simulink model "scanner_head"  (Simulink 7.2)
settings: Solver=FixedStepDiscrete  SolverMode=SingleTasking  StartTime=0  StopTime=500  FixedStep=0.004  RelTol=1e-3
PreLoadFcn:
  | scanner_head_prm;
  | xlsreadsdo('nxtscanner.xls','mpt');
undefined symbols (not defined in the file or in its folder): BACKLASH_ADJUST, RELEASE_TOUCH_SENSOR, SCAN_EDGE, SCAN_F_TIMEOUT, SCAN_INITIALIZE_PWM, SCAN_INITIALIZE_TIMEOUT, SCAN_L_MAX_PWM, SCAN_L_MIN_PWM, SCAN_L_TIMEOUT, SCAN_R_MAX_PWM, SCAN_R_MIN_PWM, SCAN_R_TIMEOUT, SCAN_START, ScannerBufferInfoEnum, sigbuilder_block
libraries: simulink x1

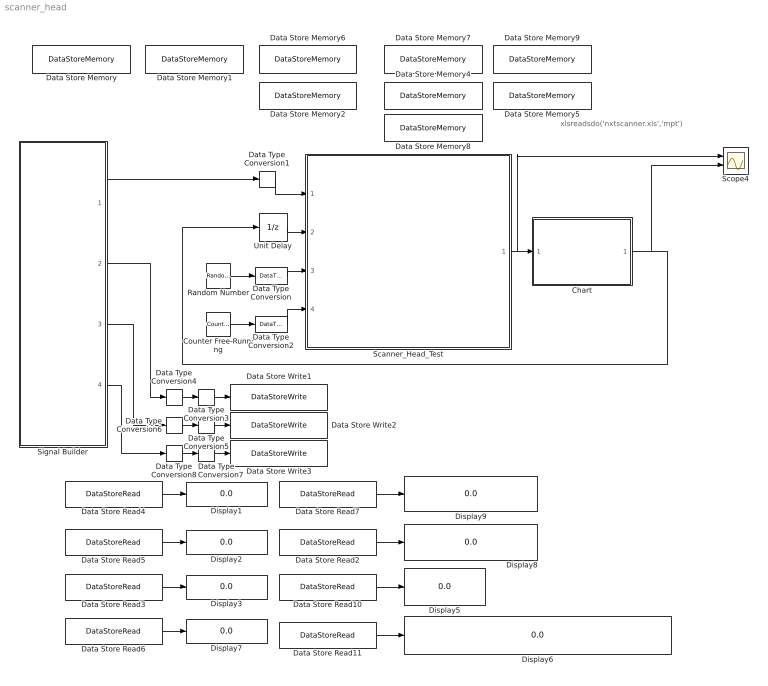
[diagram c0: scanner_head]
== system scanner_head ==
  note: xlsreadsdo('nxtscanner.xls','mpt')
  Chart : Stateflow chart
  Counter Free-Running : simulink/Sources/Counter Free-Running  SystemSampleTime=-1  NumBits=32  tsamp=-1
  Data Store Memory : DataStoreMemory  DataStoreName=ControlMode  ReadBeforeWriteMsg=warning  WriteAfterWriteMsg=warning  WriteAfterReadMsg=warning  InitialValue=ControlModeEnum.INITIALIZE  DataType=Specify via dialog  OutDataType=Enum: ControlModeEnum  OutDataTypeStr=Enum: ControlModeEnum
  Data Store Memory1 : DataStoreMemory  DataStoreName=ErrorCode  ReadBeforeWriteMsg=warning  WriteAfterWriteMsg=warning  WriteAfterReadMsg=warning  InitialValue=ErrorCodeEnum.NO_ERROR  DataType=Specify via dialog  OutDataType=Enum: ErrorCodeEnum  OutDataTypeStr=Enum: ErrorCodeEnum
  Data Store Memory2 : DataStoreMemory  DataStoreName=FeedMode  ReadBeforeWriteMsg=warning  WriteAfterWriteMsg=warning  WriteAfterReadMsg=warning  InitialValue=FeedModeEnum.FEED_IDLE  DataType=Specify via dialog  OutDataType=Enum: FeedModeEnum  OutDataTypeStr=Enum: FeedModeEnum
  Data Store Memory4 : DataStoreMemory  DataStoreName=ScannerBuffer_Number  ReadBeforeWriteMsg=warning  WriteAfterWriteMsg=warning  WriteAfterReadMsg=warning  InitialValue=[0;0]  DataType=uint8  OutDataType=Enum: FeedModeEnum  OutDataTypeStr=uint8
  Data Store Memory5 : DataStoreMemory  DataStoreName=ScannerBuffer_Data  ReadBeforeWriteMsg=warning  WriteAfterWriteMsg=warning  WriteAfterReadMsg=warning  InitialValue=[0 0 0 0 0 0 0 0 0 0 0 0 0 0 0 0 0 0 0 0 0 0 0 0 0 0 0 0 0 0; 0 0 0 0 0 0 0 0 0 0 0 0 0 0 0 0 0 0 0 0 0 0 0 0 0 0 0 0 0 0]  DataType=uint16  OutDataType=Enum: FeedModeEnum  OutDataTypeStr=uint16
  Data Store Memory6 : DataStoreMemory  DataStoreName=ScanMode  ReadBeforeWriteMsg=warning  WriteAfterWriteMsg=warning  WriteAfterReadMsg=warning  InitialValue=ScanModeEnum.SCAN_INIT  DataType=Specify via dialog  OutDataType=Enum: ScanModeEnum  OutDataTypeStr=Enum: ScanModeEnum
  Data Store Memory7 : DataStoreMemory  DataStoreName=ScannerBuffer_Info  ReadBeforeWriteMsg=warning  WriteAfterWriteMsg=warning  WriteAfterReadMsg=warning  InitialValue=[ScannerBufferInfoEnum.TRANS_FINISH;ScannerBufferInfoEnum.TRANS_FINISH]  DataType=Specify via dialog  OutDataType=Enum: ScannerBufferInfoEnum  OutDataTypeStr=Enum: ScannerBufferInfoEnum
  Data Store Memory8 : DataStoreMemory  DataStoreName=ScannerBuffer_Pnum  ReadBeforeWriteMsg=warning  WriteAfterWriteMsg=warning  WriteAfterReadMsg=warning  InitialValue=[0;0]  DataType=uint8  OutDataType=Enum: FeedModeEnum  OutDataTypeStr=uint8
  Data Store Memory9 : DataStoreMemory  DataStoreName=ScannerBuffer_Status  ReadBeforeWriteMsg=warning  WriteAfterWriteMsg=warning  WriteAfterReadMsg=warning  InitialValue=[0 ;0]  DataType=uint16  OutDataType=Enum: ScannerBufferStatusEnum  OutDataTypeStr=uint16
  Data Store Read10 : DataStoreRead  DataStoreName=ScannerBuffer_Number  SampleTime=0.004
  Data Store Read11 : DataStoreRead  DataStoreName=ScannerBuffer_Data  SampleTime=0.004
  Data Store Read2 : DataStoreRead  DataStoreName=ScannerBuffer_Status  SampleTime=0.004
  Data Store Read3 : DataStoreRead  DataStoreName=ErrorCode  SampleTime=0.004
  Data Store Read4 : DataStoreRead  DataStoreName=ControlMode  SampleTime=0.004
  Data Store Read5 : DataStoreRead  DataStoreName=FeedMode  SampleTime=0.004
  Data Store Read6 : DataStoreRead  DataStoreName=ScanMode  SampleTime=0.004
  Data Store Read7 : DataStoreRead  DataStoreName=ScannerBuffer_Info  SampleTime=0.004
  Data Store Write1 : DataStoreWrite  DataStoreName=ControlMode  SampleTime=-1
  Data Store Write2 : DataStoreWrite  DataStoreName=FeedMode  SampleTime=-1
  Data Store Write3 : DataStoreWrite  DataStoreName=ErrorCode  SampleTime=-1
  Data Type Conversion : DataTypeConversion  OutDataTypeMode=uint16  OutDataType=sfix(16)  OutScaling=2^0  OutDataTypeStr=uint16
  Data Type Conversion{1,3,5,7} (4 alike) : DataTypeConversion  OutDataType=sfix(16)  OutScaling=2^0
  Data Type Conversion2 : DataTypeConversion  OutDataTypeMode=uint32  OutDataType=sfix(16)  OutScaling=2^0  OutDataTypeStr=uint32
  Data Type Conversion4 : DataTypeConversion  OutDataTypeMode=int8  OutDataType=sfix(16)  OutScaling=2^0  OutDataTypeStr=int8
  Data Type Conversion6 : DataTypeConversion  OutDataTypeMode=int8  OutDataType=sfix(16)  OutScaling=2^0  OutDataTypeStr=int8
  Data Type Conversion8 : DataTypeConversion  OutDataTypeMode=int8  OutDataType=sfix(16)  OutScaling=2^0  OutDataTypeStr=int8
  Display{1..3,5..9} (8 alike) : Display
  Random Number : RandomNumber  Mean=1000  Variance=500  SampleTime=0.004
  Scanner_Head_Test : Subsystem
  Scope4 : Scope  NumInputPorts=2
  Signal Builder : Subsystem  Tag=STV Subsys  LoadFcn=sigbuilder_block('load',[199.5 39.75 666 664.5 ]);  StartFcn=sigbuilder_block('start');  StopFcn=sigbuilder_block('stop');  ClipboardFcn=sigbuilder_block('clipboard');
  Unit Delay : UnitDelay  SampleTime=-1
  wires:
  Random Number/1 -> Data Type Conversion/1
  Data Store Read3/1 -> Display3/1
  Data Type Conversion/1 -> Scanner_Head_Test/3(LightSensor)
  Data Store Read4/1 -> Display1/1
  Data Store Read5/1 -> Display2/1
  Data Store Read10/1 -> Display5/1
  Data Store Read11/1 -> Display6/1
  Data Store Read6/1 -> Display7/1
  Chart/1(Encoder_test) -> Unit Delay/1, Scope4/2
  Scanner_Head_Test/1(PWM) -> Chart/1(pwm), Scope4/1
  Data Store Read2/1 -> Display8/1
  Data Store Read7/1 -> Display9/1
  Unit Delay/1 -> Scanner_Head_Test/2(Encoder)
  Counter Free-Running/1 -> Data Type Conversion2/1
  Data Type Conversion2/1 -> Scanner_Head_Test/4(SystemClock)
  Signal Builder/1(SW) -> Data Type Conversion1/1
  Signal Builder/4(ErrorCode) -> Data Type Conversion8/1
  Signal Builder/2(ControlMode) -> Data Type Conversion4/1
  Data Type Conversion3/1 -> Data Store Write1/1
  Data Type Conversion4/1 -> Data Type Conversion3/1
  Data Type Conversion6/1 -> Data Type Conversion5/1
  Data Type Conversion5/1 -> Data Store Write2/1
  Signal Builder/3(FeedMode) -> Data Type Conversion6/1
  Data Type Conversion7/1 -> Data Store Write3/1
  Data Type Conversion8/1 -> Data Type Conversion7/1
  Data Type Conversion1/1 -> Scanner_Head_Test/1(SW)

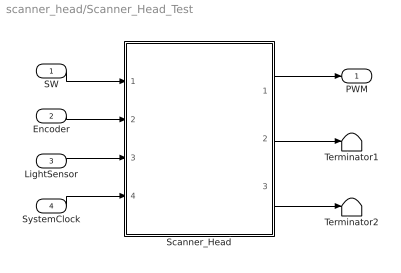
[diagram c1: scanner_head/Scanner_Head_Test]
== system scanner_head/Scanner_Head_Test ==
  SW : Inport
  Encoder : Inport  Port=2
  LightSensor : Inport  Port=3
  SystemClock : Inport  Port=4
  Scanner_Head : Subsystem  TreatAsAtomicUnit=on
  Terminator1 : Terminator
  Terminator2 : Terminator
  PWM : Outport  OutDataType=sfix(16)  OutScaling=2^0
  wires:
  SW/1 -> Scanner_Head/1(Touch)
  Encoder/1 -> Scanner_Head/2(Encoder)
  LightSensor/1 -> Scanner_Head/3(LightSensor)
  Scanner_Head/1(PWM) -> PWM/1
  Scanner_Head/2(now_position) -> Terminator1/1
  SystemClock/1 -> Scanner_Head/4(SystemClock)
  Scanner_Head/3(encoder_base) -> Terminator2/1

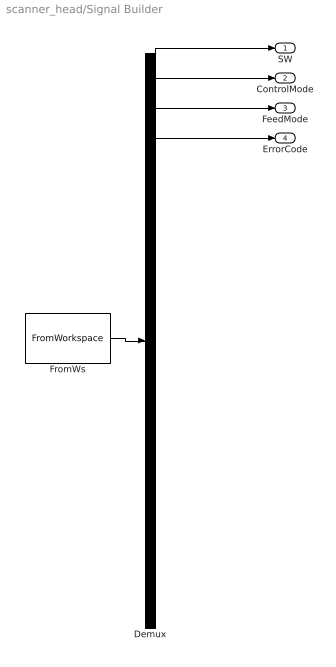
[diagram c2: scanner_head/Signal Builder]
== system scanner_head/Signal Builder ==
  Demux : Demux  Tag=STV Demux
  FromWs : FromWorkspace  Tag=STV FromWs  VariableName=tuvar  SampleTime=0  SigBuilderData=DataTag0  VnvData=DataTag1
  SW : Outport  Tag=STV Outport  OutDataType=sfix(16)  OutScaling=2^0
  ControlMode : Outport  Tag=STV Outport  Port=2
  FeedMode : Outport  Tag=STV Outport  Port=3
  ErrorCode : Outport  Tag=STV Outport  Port=4
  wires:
  FromWs/1 -> Demux/1
  Demux/1 -> SW/1
  Demux/2 -> ControlMode/1
  Demux/3 -> FeedMode/1
  Demux/4 -> ErrorCode/1

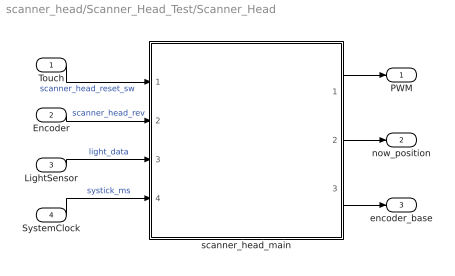
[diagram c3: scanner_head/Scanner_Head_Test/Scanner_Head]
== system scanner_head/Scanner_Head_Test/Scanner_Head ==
  Touch : Inport
  Encoder : Inport  Port=2
  LightSensor : Inport  Port=3
  SystemClock : Inport  Port=4
  scanner_head_main : Stateflow chart
  PWM : Outport  OutDataType=sfix(16)  OutScaling=2^0
  now_position : Outport  Port=2  OutDataType=sfix(16)  OutScaling=2^0
  encoder_base : Outport  Port=3  OutDataType=sfix(16)  OutScaling=2^0
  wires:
  Touch/1 -> scanner_head_main/1(touch_in)  "scanner_head_reset_sw"
  Encoder/1 -> scanner_head_main/2(encoder_in)  "scanner_head_rev"
  LightSensor/1 -> scanner_head_main/3(lightsensor_in)  "light_data"
  scanner_head_main/1(pwm_out) -> PWM/1
  scanner_head_main/2(now_position) -> now_position/1
  scanner_head_main/3(encoder_base) -> encoder_base/1
  SystemClock/1 -> scanner_head_main/4(system_clock_in)  "systick_ms"

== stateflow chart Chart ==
  (default) -> (junction 3)
  (junction 3) -> (junction 4) : [pwm < 0]
  (junction 4) -> (junction 5) : { % 右へ移動 Encoder_test = Encoder_test -3; }
  (junction 6) -> (junction 9)
  (junction 5) -> (junction 8)
  (junction 8) -> (junction 9)
  (junction 7) -> (junction 8) : { % 左へ移動 Encoder_test = Encoder_test +3; }
  (junction 3) -> (junction 6)
  (junction 6) -> (junction 7) : [pwm > 0]
  (junction 9) -> (junction 13)
  (junction 13) -> (junction 12) : [FeedMode == FEED_PAPERFEED ]
  (junction 12) -> (junction 11) : { % 強制紙送り完了させる FeedMode = FEED_IDLE; }
  (junction 11) -> (junction 10)
  (junction 13) -> (junction 10)
  (junction 10) -> (junction 14)
  (junction 14) -> (junction 15) : [ScannerBuffer_Info[0] == FULL_UP]
  (junction 15) -> (junction 16) : { ScannerBuffer_Info[0] = TRANS_FINISH; ScannerBuffer_Number[0] = 0; }
  (junction 16) -> (junction 17)
  (junction 14) -> (junction 17)
  (junction 19) -> (junction 20) : { ScannerBuffer_Info[1] = TRANS_FINISH; ScannerBuffer_Number[1] = 0; }
  (junction 17) -> (junction 18)
  (junction 18) -> (junction 19) : [ScannerBuffer_Info[1] == FULL_UP]
  (junction 20) -> (junction 21)
  (junction 18) -> (junction 21)

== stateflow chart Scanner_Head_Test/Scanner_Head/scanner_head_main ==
  state paper_feed_init [function]
    (default) -> (junction 125)
  state scan_usb_stop [function]
    (default) -> (junction 78) : { pwm_out = 0; ScannerBuffer_Info[select]=FULL_UP; ScannerBuffer_Status[select] = status_maker(1, start_flg, 1, DIR_R); ScannerBuffer_Pnum[select] = packet_cnt + 1; }
  state SCAN_INIT_POSITION/
    en:
    % initial position serch for scanner head
    scan_environment();
    scan_timeover_set();
    scan_start_position_seek();
    du:
    scan_start_position_seek();
  state paper_feed [function]
    (junction 97) -> (junction 80) : { % paper feeding }
    (junction 88) -> (junction 80)
    (junction 99) -> (junction 88) : { % paper feed finished ScanMode = SCAN_SCAN; }
    (default) -> (junction 97)
    (junction 97) -> (junction 99) : [FeedMode == FEED_IDLE]
  state SCAN_ERROR/
    en:
    % system malfunction
    pwm_out = 0;
  state SCAN_ERROR_STOP/
    en:
    % scanner head system error
    scan_usb_stop();
    ErrorCode = ERROR_001;
  state scan_environment [function]
    (default) -> (junction 108) : { start_flg = 1; select = 0; line_cnt=0; line_end_flg = 0; packet_cnt = 0; scan_init_end_flg = 0; }
  state scan_init(arg_target_dir) [function]
    (junction 120) -> (junction 126) : { % for left-scanning start_position = encoder_in +BACKLASH_ADJUST; }
    (junction 133) -> (junction 120) : % request of scan direction [arg_target_dir == DIR_L]
    (junction 126) -> (junction 82)
    (junction 83) -> (junction 82) : { % for right-scanning(only after initialize) start_position = encoder_in -RELEASE_TOUCH_SENSOR -BACKLASH_ADJUST; }
    (junction 105) -> (junction 83) : [start_flg == 1]
    (default) -> (junction 133) : { line_end_flg = 0; packet_cnt = 0; ScanMode = SCAN_SCAN; encoder_base =SCAN_START; }
    (junction 133) -> (junction 105)
    (junction 105) -> (junction 128) : { % for right-scanning(nomaly) start_position = encoder_in -BACKLASH_ADJUST; }
    (junction 82) -> (junction 128)
  state out = status_maker(arg_elp, arg_start, arg_stop, arg_dir) [function]
    (junction 122) -> (junction 140) : { out = out + 16; }
    (junction 96) -> (junction 93) : { out = out + 4; }
    (junction 86) -> (junction 94)
    (junction 93) -> (junction 94)
    (junction 103) -> (junction 102)
    (junction 95) -> (junction 102)
    (junction 100) -> (junction 95) : { out = out + 8; }
    (junction 86) -> (junction 96) : [arg_stop == 1]
    (junction 102) -> (junction 86)
    (junction 103) -> (junction 100) : [arg_start == 1]
    (default) -> (junction 123) : { out = 1; }
    (junction 140) -> (junction 124)
    (junction 123) -> (junction 122) : [arg_elp == 1]
    (junction 124) -> (junction 103)
    (junction 123) -> (junction 124)
    (junction 94) -> (junction 162)
    (junction 160) -> (junction 161)
    (junction 162) -> (junction 161)
    (junction 163) -> (junction 160) : { out = out + 2; }
    (junction 162) -> (junction 163) : [arg_dir == 1]
  state scan_control_right [function]
    (default) -> (junction 149) : { % right-scanning now_position = start_position - encoder_in; pwm_out = get_pwm_value(DIR_R, now_position, SCAN_R_MAX_PWM, SCAN_R_MIN_PWM); }
    (junction 77) -> (junction 107) : % buffer full detection [ScannerBuffer_Number[select] >= 30]
    (junction 138) -> (junction 136) : { % send final packet line_end_flg = 1; line_cnt ++; ScannerBuffer_Info[select]=FULL_UP; packet_cnt ++; ScannerBuffer_Pnum[select] = packet_cnt; }
    (junction 89) -> (junction 91)
    (junction 136) -> (junction 81) : [line_cnt >=127]
    (junction 135) -> (junction 77) : { % next scan position encoder_base = encoder_base + 2; % store data ScannerBuffer_Data[select][ScannerBuffer_Number[select]] = lightsensor_in; ScannerBuffer_Number[select]++; ScannerBuffer_Info[select] = STORING; }
    (junction 109) -> (junction 106) : % edge detection [pwm_out == 0]
    (junction 81) -> (junction 91) : { ScannerBuffer_Status[select] = status_maker(1, start_flg, 1, DIR_R); ScanMode = SCAN_INIT; FINISH; }
    (junction 131) -> (junction 113)
    (junction 107) -> (junction 118) : { packet_cnt ++; ScannerBuffer_Info[select]=FULL_UP; ScannerBuffer_Status[select] = status_maker(0, start_flg, 0, DIR_R); ScannerBuffer_Pnum[select] = packet_cnt; start_flg=0; }
    (junction 129) -> (junction 111)
    (junction 111) -> (junction 112)
    (junction 112) -> (junction 89)
    (junction 91) -> (junction 90)
    (junction 117) -> (junction 111) : { % full of buffer1 select = 0; }
    (junction 118) -> (junction 112) : { % full of buffer0 select = 1; }
    (junction 118) -> (junction 117) : [select == 1]
    (junction 77) -> (junction 89)
    (junction 131) -> (junction 130) : [(now_position > SCAN_START && now_position > encoder_base)]
    (junction 149) -> (junction 109)
    (junction 109) -> (junction 131)
    (junction 130) -> (junction 134)
    (junction 134) -> (junction 135) : [now_position <= (SCAN_EDGE - SCAN_START)]
    (junction 136) -> (junction 90) : { ScannerBuffer_Status[select] = status_maker(1, start_flg, 0, DIR_R); }
    (junction 90) -> (junction 139)
    (junction 137) -> (junction 138) : [line_end_flg == 0]
    (junction 134) -> (junction 137)
    (junction 137) -> (junction 139)
    (junction 139) -> (junction 113)
    (junction 106) -> (junction 129) : { % right-scanning finished FeedMode = FEED_PAPERFEED; ScanMode = SCAN_FEED; }
    (junction 142) -> (junction 129)
    (junction 149) -> (junction 144) : [touch_in == 1 && now_position > 0]
    (junction 144) -> (junction 142) : { STOP; }
  state scan_start_position_seek [function]
    (junction 127) -> (junction 119) : { % initialize finished pwm_out = 0; ScanMode = SCAN_IDLE; scan_init_end_flg = 1; }
    (default) -> (junction 98)
    (junction 98) -> (junction 116)
    (junction 115) -> (junction 114) : { STOP; }
    (junction 98) -> (junction 127) : [touch_in == 1]
    (junction 114) -> (junction 121)
    (junction 116) -> (junction 121) : { % now moving pwm_out = SCAN_INITIALIZE_PWM; scan_timeover_check(SCAN_INITIALIZE_TIMEOUT, system_clock_in); }
    (junction 116) -> (junction 115) : [scan_init_end_flg == 1]
    (junction 119) -> (junction 114)
  state scan_timeover_set [function]
    (default) -> (junction 146) : { start_time = system_clock_in; }
  state INIT_ERROR_STOP/
    en:
    % error
    pwm_out = 0;
    ErrorCode = ERROR_001;
  state scan_timeover_check(arg_target_ms, arg_now_clock) [function]
    (junction 132) -> (junction 143) : [arg_target_ms < (arg_now_clock - start_time)]
    (junction 143) -> (junction 150) : { % time over STOP; }
    (junction 132) -> (junction 110)
    (default) -> (junction 132)
    (junction 150) -> (junction 110)
  state SCAN_NORMAL/
    state SCAN_RIGHT/
      % scanner head right-scanning
      en:
      scan_init(DIR_R);
      scan_timeover_set();
      scan_control_right();
      du:
      scan_control_right();
      scan_timeover_check(SCAN_R_TIMEOUT, system_clock_in);
    state SCAN_LEFT/
      % scanner head left-scanning
      en:
      scan_init(DIR_L);
      scan_timeover_set();
      scan_control_left();
      du:
      scan_control_left();
      scan_timeover_check(SCAN_L_TIMEOUT, system_clock_in);
    state PAPER_FEED_L/
      % paper feed at left edge
      en:
      paper_feed_init();
      scan_timeover_set();
      paper_feed();
      du:
      paper_feed();
      scan_timeover_check(SCAN_F_TIMEOUT, system_clock_in);
    SCAN_RIGHT -> SCAN_LEFT : [ScanMode == SCAN_FEED] {ScanMode = SCAN_SCAN;}
    (default) -> SCAN_RIGHT
    PAPER_FEED_L -> SCAN_RIGHT : [ScanMode == SCAN_SCAN]
    SCAN_LEFT -> PAPER_FEED_L : [ScanMode == SCAN_FEED]
  state pwm = get_pwm_value(arg_dir, arg_position, arg_max, arg_min) [function]
    (junction 101) -> (junction 104)
    (junction 101) -> (junction 76) : [arg_position < 0]
    (junction 85) -> (junction 151) : { % over position pwm = 0; }
    (junction 84) -> (junction 87) : { % sine change for right-scanning pwm = (-1)*pwm; }
    (junction 158) -> (junction 84) : [arg_dir == 0]
    (junction 104) -> (junction 85) : [arg_position > SCAN_EDGE]
    (default) -> (junction 101) : /* scanner head speed control */
    (junction 104) -> (junction 141)
    (junction 141) -> (junction 145) : { % accel & constant speed pwm = arg_max; }
    (junction 141) -> (junction 148) : [arg_position > (SCAN_EDGE - 60)]
    (junction 76) -> (junction 147) : { % before start position pwm = arg_max; }
    (junction 148) -> (junction 153) : { % brake control pwm = arg_min; }
    (junction 153) -> (junction 145)
    (junction 147) -> (junction 151)
    (junction 151) -> (junction 153)
    (junction 87) -> (junction 152)
    (junction 145) -> (junction 158)
    (junction 158) -> (junction 152)
  state scan_control_left [function]
    (junction 157) -> (junction 159) : { % finish left-scanning(only move) %FeedMode = FEED_IDLE; ScanMode = SCAN_FEED; }
    (junction 92) -> (junction 159)
    (junction 156) -> (junction 79)
    (default) -> (junction 154) : { % left-scanning now_position = encoder_in - start_position; pwm_out = get_pwm_value(DIR_L, now_position, SCAN_L_MAX_PWM, SCAN_L_MIN_PWM); }
    (junction 159) -> (junction 79)
    (junction 154) -> (junction 155) : [touch_in == 1 && now_position > 0]
    (junction 154) -> (junction 156)
    (junction 155) -> (junction 92) : { RUNTIME_ERROR; }
    (junction 156) -> (junction 157) : % edge detection [pwm_out == 0]
  state RUNTIME_ERROR_STOP/
    en:
    % for polyspace demonstration
    pwm_out = 7;
    ErrorCode = ERROR_001;
    ScannerBuffer_Info[select]=FULL_UP;
    ScannerBuffer_Status[select] = status_maker(1, start_flg, 1, DIR_L);
    ScannerBuffer_Pnum[select] = polyspace[pwm_out];
  SCAN_INIT_POSITION -> SCAN_NORMAL : [ControlMode == SCAN && ScanMode == SCAN_IDLE]
  SCAN_NORMAL -> SCAN_ERROR : [ControlMode == ERROR] { scan_usb_stop(); }
  (default) -> SCAN_INIT_POSITION
  SCAN_NORMAL -> SCAN_INIT_POSITION : [ControlMode != ERROR && ControlMode != SCAN] { scan_usb_stop(); }
  SCAN_INIT_POSITION -> SCAN_ERROR : [ControlMode == ERROR]
  SCAN_NORMAL -> RUNTIME_ERROR_STOP : RUNTIME_ERROR
  SCAN_NORMAL -> SCAN_INIT_POSITION : FINISH
  INIT_ERROR_STOP -> SCAN_ERROR : [ControlMode == ERROR]
  SCAN_INIT_POSITION -> INIT_ERROR_STOP : STOP
  SCAN_NORMAL -> SCAN_ERROR_STOP : STOP
